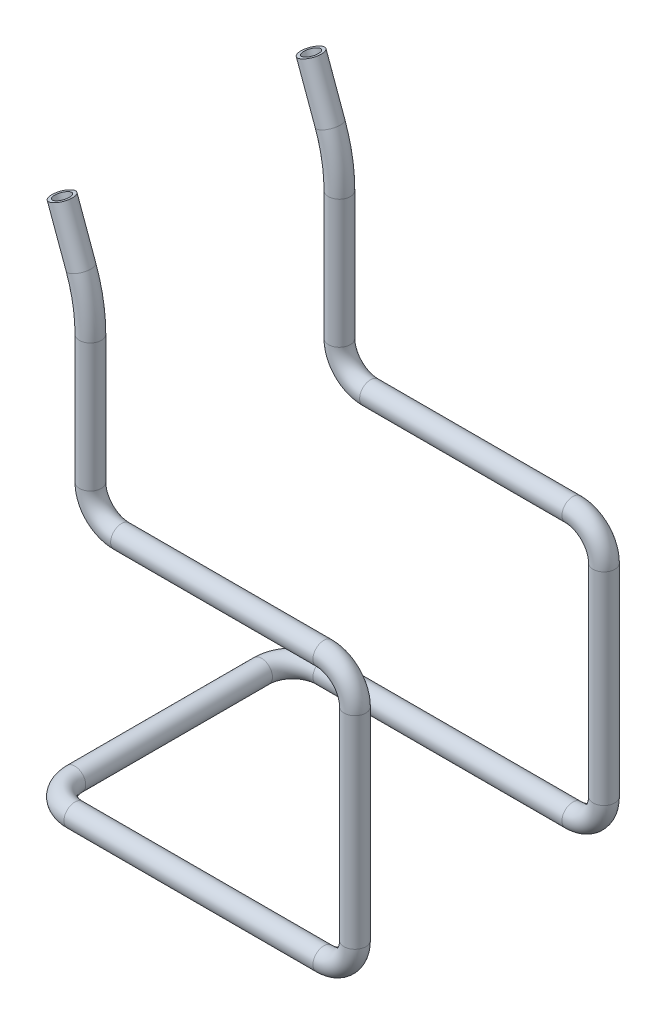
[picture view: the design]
ISO-10303-21;
HEADER;
FILE_DESCRIPTION(('STEP AP214'),'2;1');
FILE_NAME('part.step','',(''),(''),'','','');
FILE_SCHEMA(('AUTOMOTIVE_DESIGN { 1 0 10303 214 1 1 1 1 }'));
ENDSEC;
DATA;
#1=APPLICATION_CONTEXT('core data for automotive mechanical design processes');
#2=APPLICATION_PROTOCOL_DEFINITION('international standard','automotive_design',2000,#1);
#3=PRODUCT_CONTEXT('',#1,'mechanical');
#4=PRODUCT('Part','Part','',(#3));
#5=PRODUCT_RELATED_PRODUCT_CATEGORY('part','',(#4));
#6=PRODUCT_DEFINITION_FORMATION('','',#4);
#7=PRODUCT_DEFINITION_CONTEXT('part definition',#1,'design');
#8=PRODUCT_DEFINITION('design','',#6,#7);
#9=PRODUCT_DEFINITION_SHAPE('','',#8);
#10=(LENGTH_UNIT() NAMED_UNIT(*) SI_UNIT(.MILLI.,.METRE.));
#11=(NAMED_UNIT(*) PLANE_ANGLE_UNIT() SI_UNIT($,.RADIAN.));
#12=(NAMED_UNIT(*) SI_UNIT($,.STERADIAN.) SOLID_ANGLE_UNIT());
#13=UNCERTAINTY_MEASURE_WITH_UNIT(LENGTH_MEASURE(1.E-05),#10,'distance_accuracy_value','');
#14=(GEOMETRIC_REPRESENTATION_CONTEXT(3) GLOBAL_UNCERTAINTY_ASSIGNED_CONTEXT((#13)) GLOBAL_UNIT_ASSIGNED_CONTEXT((#10,
#11,#12)) REPRESENTATION_CONTEXT('',''));
#15=CARTESIAN_POINT('',(0.,0.,0.));
#16=DIRECTION('',(0.,0.,1.));
#17=DIRECTION('',(1.,0.,0.));
#18=AXIS2_PLACEMENT_3D('',#15,#16,#17);
#19=CARTESIAN_POINT('',(11.9846310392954,153.28465813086,40.));
#20=DIRECTION('',(-0.34202014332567,0.939692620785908,0.));
#21=DIRECTION('',(-0.939692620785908,-0.34202014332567,0.));
#22=AXIS2_PLACEMENT_3D('',#19,#20,#21);
#23=CYLINDRICAL_SURFACE('',#22,3.5);
#24=CARTESIAN_POINT('',(11.9846310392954,153.28465813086,40.));
#25=DIRECTION('',(-0.34202014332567,0.939692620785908,0.));
#26=DIRECTION('',(-0.939692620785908,-0.34202014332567,0.));
#27=AXIS2_PLACEMENT_3D('',#24,#25,#26);
#28=CIRCLE('',#27,3.5);
#29=CARTESIAN_POINT('',(15.2735552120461,154.4817286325,39.9999999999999));
#30=VERTEX_POINT('',#29);
#31=EDGE_CURVE('E37',#30,#30,#28,.T.);
#32=ORIENTED_EDGE('',*,*,#31,.T.);
#33=EDGE_LOOP('',(#32));
#34=FACE_BOUND('',#33,.T.);
#35=CARTESIAN_POINT('',(5.90074414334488,170.,40.0000000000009));
#36=DIRECTION('',(-0.34202014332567,0.939692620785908,0.));
#37=DIRECTION('',(-0.939692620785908,-0.342020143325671,0.));
#38=AXIS2_PLACEMENT_3D('',#35,#36,#37);
#39=CIRCLE('',#38,3.5);
#40=CARTESIAN_POINT('',(2.61181997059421,168.80292949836,40.0000000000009));
#41=VERTEX_POINT('',#40);
#42=EDGE_CURVE('E10',#41,#41,#39,.T.);
#43=ORIENTED_EDGE('',*,*,#42,.F.);
#44=EDGE_LOOP('',(#43));
#45=FACE_BOUND('',#44,.T.);
#46=ADVANCED_FACE('F30',(#34,#45),#23,.T.);
#47=CARTESIAN_POINT('',(-35.,136.183650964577,40.0000000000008));
#48=DIRECTION('',(0.,0.,1.));
#49=DIRECTION('',(1.,0.,0.));
#50=AXIS2_PLACEMENT_3D('',#47,#48,#49);
#51=TOROIDAL_SURFACE('',#50,50.,3.5);
#52=CARTESIAN_POINT('',(15.,136.183650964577,39.9999999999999));
#53=DIRECTION('',(0.,-1.,0.));
#54=DIRECTION('',(0.,0.,-1.));
#55=AXIS2_PLACEMENT_3D('',#52,#53,#54);
#56=CIRCLE('',#55,3.5);
#57=CARTESIAN_POINT('',(18.5,136.183650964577,39.9999999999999));
#58=VERTEX_POINT('',#57);
#59=EDGE_CURVE('E41',#58,#58,#56,.F.);
#60=CARTESIAN_POINT('',(-35.,136.183650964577,40.0000000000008));
#61=DIRECTION('',(0.,0.,1.));
#62=DIRECTION('',(1.,0.,0.));
#63=AXIS2_PLACEMENT_3D('',#60,#61,#62);
#64=CIRCLE('',#63,53.5);
#65=EDGE_CURVE('',#58,#30,#64,.T.);
#66=ORIENTED_EDGE('',*,*,#59,.T.);
#67=ORIENTED_EDGE('',*,*,#31,.F.);
#68=ORIENTED_EDGE('',*,*,#65,.T.);
#69=ORIENTED_EDGE('',*,*,#65,.F.);
#70=EDGE_LOOP('',(#66,#68,#67,#69));
#71=FACE_BOUND('',#70,.T.);
#72=ADVANCED_FACE('F198',(#71),#51,.T.);
#73=CARTESIAN_POINT('',(15.,95.,40.));
#74=DIRECTION('',(0.,1.,0.));
#75=DIRECTION('',(0.,0.,1.));
#76=AXIS2_PLACEMENT_3D('',#73,#74,#75);
#77=CYLINDRICAL_SURFACE('',#76,3.5);
#78=CARTESIAN_POINT('',(15.,95.,40.));
#79=DIRECTION('',(0.,1.,0.));
#80=DIRECTION('',(0.,0.,1.));
#81=AXIS2_PLACEMENT_3D('',#78,#79,#80);
#82=CIRCLE('',#81,3.5);
#83=CARTESIAN_POINT('',(11.5,95.,40.));
#84=VERTEX_POINT('',#83);
#85=EDGE_CURVE('E46',#84,#84,#82,.T.);
#86=ORIENTED_EDGE('',*,*,#85,.T.);
#87=EDGE_LOOP('',(#86));
#88=FACE_BOUND('',#87,.T.);
#89=ORIENTED_EDGE('',*,*,#59,.F.);
#90=EDGE_LOOP('',(#89));
#91=FACE_BOUND('',#90,.T.);
#92=ADVANCED_FACE('F203',(#88,#91),#77,.T.);
#93=CARTESIAN_POINT('',(25.,95.,40.));
#94=DIRECTION('',(0.,0.,-1.));
#95=DIRECTION('',(-1.,0.,0.));
#96=AXIS2_PLACEMENT_3D('',#93,#94,#95);
#97=TOROIDAL_SURFACE('',#96,10.,3.5);
#98=CARTESIAN_POINT('',(25.,85.,40.));
#99=DIRECTION('',(1.,0.,0.));
#100=DIRECTION('',(0.,1.,0.));
#101=AXIS2_PLACEMENT_3D('',#98,#99,#100);
#102=CIRCLE('',#101,3.5);
#103=CARTESIAN_POINT('',(25.,81.5,40.));
#104=VERTEX_POINT('',#103);
#105=EDGE_CURVE('E54',#104,#104,#102,.F.);
#106=CARTESIAN_POINT('',(25.,95.,40.));
#107=DIRECTION('',(0.,0.,-1.));
#108=DIRECTION('',(-1.,0.,0.));
#109=AXIS2_PLACEMENT_3D('',#106,#107,#108);
#110=CIRCLE('',#109,13.5);
#111=EDGE_CURVE('',#104,#84,#110,.T.);
#112=ORIENTED_EDGE('',*,*,#105,.T.);
#113=ORIENTED_EDGE('',*,*,#85,.F.);
#114=ORIENTED_EDGE('',*,*,#111,.T.);
#115=ORIENTED_EDGE('',*,*,#111,.F.);
#116=EDGE_LOOP('',(#112,#114,#113,#115));
#117=FACE_BOUND('',#116,.T.);
#118=ADVANCED_FACE('F213',(#117),#97,.T.);
#119=CARTESIAN_POINT('',(90.,85.,40.));
#120=DIRECTION('',(-1.,0.,0.));
#121=DIRECTION('',(0.,0.,1.));
#122=AXIS2_PLACEMENT_3D('',#119,#120,#121);
#123=CYLINDRICAL_SURFACE('',#122,3.5);
#124=CARTESIAN_POINT('',(90.,85.,40.));
#125=DIRECTION('',(-1.,0.,0.));
#126=DIRECTION('',(0.,0.,1.));
#127=AXIS2_PLACEMENT_3D('',#124,#125,#126);
#128=CIRCLE('',#127,3.5);
#129=CARTESIAN_POINT('',(90.,88.5,40.));
#130=VERTEX_POINT('',#129);
#131=EDGE_CURVE('E57',#130,#130,#128,.T.);
#132=ORIENTED_EDGE('',*,*,#131,.T.);
#133=EDGE_LOOP('',(#132));
#134=FACE_BOUND('',#133,.T.);
#135=ORIENTED_EDGE('',*,*,#105,.F.);
#136=EDGE_LOOP('',(#135));
#137=FACE_BOUND('',#136,.T.);
#138=ADVANCED_FACE('F217',(#134,#137),#123,.T.);
#139=CARTESIAN_POINT('',(90.,75.,40.));
#140=DIRECTION('',(0.,0.,1.));
#141=DIRECTION('',(1.,0.,0.));
#142=AXIS2_PLACEMENT_3D('',#139,#140,#141);
#143=TOROIDAL_SURFACE('',#142,9.99999999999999,3.5);
#144=CARTESIAN_POINT('',(100.,75.,40.));
#145=DIRECTION('',(0.,-1.,0.));
#146=DIRECTION('',(1.,0.,0.));
#147=AXIS2_PLACEMENT_3D('',#144,#145,#146);
#148=CIRCLE('',#147,3.5);
#149=CARTESIAN_POINT('',(103.5,75.,40.));
#150=VERTEX_POINT('',#149);
#151=EDGE_CURVE('E60',#150,#150,#148,.F.);
#152=CARTESIAN_POINT('',(90.,75.,40.));
#153=DIRECTION('',(0.,0.,1.));
#154=DIRECTION('',(1.,0.,0.));
#155=AXIS2_PLACEMENT_3D('',#152,#153,#154);
#156=CIRCLE('',#155,13.5);
#157=EDGE_CURVE('',#150,#130,#156,.T.);
#158=ORIENTED_EDGE('',*,*,#151,.T.);
#159=ORIENTED_EDGE('',*,*,#131,.F.);
#160=ORIENTED_EDGE('',*,*,#157,.T.);
#161=ORIENTED_EDGE('',*,*,#157,.F.);
#162=EDGE_LOOP('',(#158,#160,#159,#161));
#163=FACE_BOUND('',#162,.T.);
#164=ADVANCED_FACE('F221',(#163),#143,.T.);
#165=CARTESIAN_POINT('',(100.,9.99999999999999,40.));
#166=DIRECTION('',(0.,1.,0.));
#167=DIRECTION('',(0.,0.,1.));
#168=AXIS2_PLACEMENT_3D('',#165,#166,#167);
#169=CYLINDRICAL_SURFACE('',#168,3.5);
#170=CARTESIAN_POINT('',(100.,9.99999999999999,40.));
#171=DIRECTION('',(0.,1.,0.));
#172=DIRECTION('',(0.,0.,1.));
#173=AXIS2_PLACEMENT_3D('',#170,#171,#172);
#174=CIRCLE('',#173,3.5);
#175=CARTESIAN_POINT('',(103.5,9.99999999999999,40.));
#176=VERTEX_POINT('',#175);
#177=EDGE_CURVE('E63',#176,#176,#174,.T.);
#178=ORIENTED_EDGE('',*,*,#177,.T.);
#179=EDGE_LOOP('',(#178));
#180=FACE_BOUND('',#179,.T.);
#181=ORIENTED_EDGE('',*,*,#151,.F.);
#182=EDGE_LOOP('',(#181));
#183=FACE_BOUND('',#182,.T.);
#184=ADVANCED_FACE('F225',(#180,#183),#169,.T.);
#185=CARTESIAN_POINT('',(90.,10.,40.));
#186=DIRECTION('',(0.,0.,1.));
#187=DIRECTION('',(1.,0.,0.));
#188=AXIS2_PLACEMENT_3D('',#185,#186,#187);
#189=TOROIDAL_SURFACE('',#188,10.,3.5);
#190=CARTESIAN_POINT('',(90.,0.,40.));
#191=DIRECTION('',(-1.,0.,0.));
#192=DIRECTION('',(0.,-1.,0.));
#193=AXIS2_PLACEMENT_3D('',#190,#191,#192);
#194=CIRCLE('',#193,3.5);
#195=CARTESIAN_POINT('',(90.,-3.5,40.));
#196=VERTEX_POINT('',#195);
#197=EDGE_CURVE('E66',#196,#196,#194,.F.);
#198=CARTESIAN_POINT('',(90.,10.,40.));
#199=DIRECTION('',(0.,0.,1.));
#200=DIRECTION('',(1.,0.,0.));
#201=AXIS2_PLACEMENT_3D('',#198,#199,#200);
#202=CIRCLE('',#201,13.5);
#203=EDGE_CURVE('',#196,#176,#202,.T.);
#204=ORIENTED_EDGE('',*,*,#197,.T.);
#205=ORIENTED_EDGE('',*,*,#177,.F.);
#206=ORIENTED_EDGE('',*,*,#203,.T.);
#207=ORIENTED_EDGE('',*,*,#203,.F.);
#208=EDGE_LOOP('',(#204,#206,#205,#207));
#209=FACE_BOUND('',#208,.T.);
#210=ADVANCED_FACE('F229',(#209),#189,.T.);
#211=CARTESIAN_POINT('',(10.,0.,40.));
#212=DIRECTION('',(1.,0.,0.));
#213=DIRECTION('',(0.,0.,-1.));
#214=AXIS2_PLACEMENT_3D('',#211,#212,#213);
#215=CYLINDRICAL_SURFACE('',#214,3.5);
#216=CARTESIAN_POINT('',(10.,0.,40.));
#217=DIRECTION('',(1.,0.,0.));
#218=DIRECTION('',(0.,0.,-1.));
#219=AXIS2_PLACEMENT_3D('',#216,#217,#218);
#220=CIRCLE('',#219,3.5);
#221=CARTESIAN_POINT('',(10.,0.,43.5));
#222=VERTEX_POINT('',#221);
#223=EDGE_CURVE('E69',#222,#222,#220,.T.);
#224=ORIENTED_EDGE('',*,*,#223,.T.);
#225=EDGE_LOOP('',(#224));
#226=FACE_BOUND('',#225,.T.);
#227=ORIENTED_EDGE('',*,*,#197,.F.);
#228=EDGE_LOOP('',(#227));
#229=FACE_BOUND('',#228,.T.);
#230=ADVANCED_FACE('F233',(#226,#229),#215,.T.);
#231=CARTESIAN_POINT('',(10.,0.,30.));
#232=DIRECTION('',(0.,1.,0.));
#233=DIRECTION('',(0.,0.,1.));
#234=AXIS2_PLACEMENT_3D('',#231,#232,#233);
#235=TOROIDAL_SURFACE('',#234,10.,3.5);
#236=CARTESIAN_POINT('',(0.,0.,30.));
#237=DIRECTION('',(0.,0.,-1.));
#238=DIRECTION('',(-1.,0.,0.));
#239=AXIS2_PLACEMENT_3D('',#236,#237,#238);
#240=CIRCLE('',#239,3.5);
#241=CARTESIAN_POINT('',(-3.5,0.,30.));
#242=VERTEX_POINT('',#241);
#243=EDGE_CURVE('E71',#242,#242,#240,.F.);
#244=CARTESIAN_POINT('',(10.,0.,30.));
#245=DIRECTION('',(0.,1.,0.));
#246=DIRECTION('',(0.,0.,1.));
#247=AXIS2_PLACEMENT_3D('',#244,#245,#246);
#248=CIRCLE('',#247,13.5);
#249=EDGE_CURVE('',#242,#222,#248,.T.);
#250=ORIENTED_EDGE('',*,*,#243,.T.);
#251=ORIENTED_EDGE('',*,*,#223,.F.);
#252=ORIENTED_EDGE('',*,*,#249,.T.);
#253=ORIENTED_EDGE('',*,*,#249,.F.);
#254=EDGE_LOOP('',(#250,#252,#251,#253));
#255=FACE_BOUND('',#254,.T.);
#256=ADVANCED_FACE('F236',(#255),#235,.T.);
#257=CARTESIAN_POINT('',(0.,0.,30.));
#258=DIRECTION('',(0.,0.,-1.));
#259=DIRECTION('',(-1.,0.,0.));
#260=AXIS2_PLACEMENT_3D('',#257,#258,#259);
#261=CYLINDRICAL_SURFACE('',#260,3.5);
#262=CARTESIAN_POINT('',(0.,0.,-30.));
#263=DIRECTION('',(0.,0.,-1.));
#264=DIRECTION('',(-1.,0.,0.));
#265=AXIS2_PLACEMENT_3D('',#262,#263,#264);
#266=CIRCLE('',#265,3.5);
#267=CARTESIAN_POINT('',(-3.5,0.,-30.));
#268=VERTEX_POINT('',#267);
#269=EDGE_CURVE('E114',#268,#268,#266,.F.);
#270=CARTESIAN_POINT('',(-3.5,0.,30.));
#271=CARTESIAN_POINT('',(-3.5,0.,29.375));
#272=CARTESIAN_POINT('',(-3.5,0.,28.75));
#273=CARTESIAN_POINT('',(-3.5,0.,27.5));
#274=CARTESIAN_POINT('',(-3.5,0.,26.875));
#275=CARTESIAN_POINT('',(-3.5,0.,25.625));
#276=CARTESIAN_POINT('',(-3.5,0.,25.));
#277=CARTESIAN_POINT('',(-3.5,0.,23.75));
#278=CARTESIAN_POINT('',(-3.5,0.,23.125));
#279=CARTESIAN_POINT('',(-3.5,0.,21.875));
#280=CARTESIAN_POINT('',(-3.5,0.,21.25));
#281=CARTESIAN_POINT('',(-3.5,0.,20.));
#282=CARTESIAN_POINT('',(-3.5,0.,19.375));
#283=CARTESIAN_POINT('',(-3.5,0.,18.125));
#284=CARTESIAN_POINT('',(-3.5,0.,17.5));
#285=CARTESIAN_POINT('',(-3.5,0.,16.25));
#286=CARTESIAN_POINT('',(-3.5,0.,15.625));
#287=CARTESIAN_POINT('',(-3.5,0.,14.375));
#288=CARTESIAN_POINT('',(-3.5,0.,13.75));
#289=CARTESIAN_POINT('',(-3.5,0.,12.5));
#290=CARTESIAN_POINT('',(-3.5,0.,11.875));
#291=CARTESIAN_POINT('',(-3.5,0.,10.625));
#292=CARTESIAN_POINT('',(-3.5,0.,10.));
#293=CARTESIAN_POINT('',(-3.5,0.,8.75));
#294=CARTESIAN_POINT('',(-3.5,0.,8.125));
#295=CARTESIAN_POINT('',(-3.5,0.,6.875));
#296=CARTESIAN_POINT('',(-3.5,0.,6.25));
#297=CARTESIAN_POINT('',(-3.5,0.,5.));
#298=CARTESIAN_POINT('',(-3.5,0.,4.375));
#299=CARTESIAN_POINT('',(-3.5,0.,3.125));
#300=CARTESIAN_POINT('',(-3.5,0.,2.5));
#301=CARTESIAN_POINT('',(-3.5,0.,1.25));
#302=CARTESIAN_POINT('',(-3.5,0.,0.624999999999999));
#303=CARTESIAN_POINT('',(-3.5,0.,-0.624999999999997));
#304=CARTESIAN_POINT('',(-3.5,0.,-1.24999999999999));
#305=CARTESIAN_POINT('',(-3.5,0.,-2.49999999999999));
#306=CARTESIAN_POINT('',(-3.5,0.,-3.12499999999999));
#307=CARTESIAN_POINT('',(-3.5,0.,-4.37499999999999));
#308=CARTESIAN_POINT('',(-3.5,0.,-4.99999999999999));
#309=CARTESIAN_POINT('',(-3.5,0.,-6.24999999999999));
#310=CARTESIAN_POINT('',(-3.5,0.,-6.87499999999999));
#311=CARTESIAN_POINT('',(-3.5,0.,-8.12499999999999));
#312=CARTESIAN_POINT('',(-3.5,0.,-8.74999999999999));
#313=CARTESIAN_POINT('',(-3.5,0.,-9.99999999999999));
#314=CARTESIAN_POINT('',(-3.5,0.,-10.625));
#315=CARTESIAN_POINT('',(-3.5,0.,-11.875));
#316=CARTESIAN_POINT('',(-3.5,0.,-12.5));
#317=CARTESIAN_POINT('',(-3.5,0.,-13.75));
#318=CARTESIAN_POINT('',(-3.5,0.,-14.375));
#319=CARTESIAN_POINT('',(-3.5,0.,-15.625));
#320=CARTESIAN_POINT('',(-3.5,0.,-16.25));
#321=CARTESIAN_POINT('',(-3.5,0.,-17.5));
#322=CARTESIAN_POINT('',(-3.5,0.,-18.125));
#323=CARTESIAN_POINT('',(-3.5,0.,-19.375));
#324=CARTESIAN_POINT('',(-3.5,0.,-20.));
#325=CARTESIAN_POINT('',(-3.5,0.,-21.25));
#326=CARTESIAN_POINT('',(-3.5,0.,-21.875));
#327=CARTESIAN_POINT('',(-3.5,0.,-23.125));
#328=CARTESIAN_POINT('',(-3.5,0.,-23.75));
#329=CARTESIAN_POINT('',(-3.5,0.,-25.));
#330=CARTESIAN_POINT('',(-3.5,0.,-25.625));
#331=CARTESIAN_POINT('',(-3.5,0.,-26.875));
#332=CARTESIAN_POINT('',(-3.5,0.,-27.5));
#333=CARTESIAN_POINT('',(-3.5,0.,-28.75));
#334=CARTESIAN_POINT('',(-3.5,0.,-29.375));
#335=CARTESIAN_POINT('',(-3.5,0.,-30.));
#336=B_SPLINE_CURVE_WITH_KNOTS('',3,(#270,#271,#272,#273,#274,#275,#276,#277,#278,#279,#280,
#281,#282,#283,#284,#285,#286,#287,#288,#289,#290,#291,#292,#293,#294,#295,#296,#297,#298,#299,
#300,#301,#302,#303,#304,#305,#306,#307,#308,#309,#310,#311,#312,#313,#314,#315,#316,#317,#318,
#319,#320,#321,#322,#323,#324,#325,#326,#327,#328,#329,#330,#331,#332,#333,#334,#335),
.UNSPECIFIED.,.F.,.F.,(4,2,2,2,2,2,2,2,2,2,2,2,2,2,2,2,2,2,2,2,2,2,2,2,2,2,2,2,2,2,2,2,4),(0.,
1.875,3.75,5.625,7.5,9.37499999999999,11.25,13.125,15.,16.875,18.75,20.625,22.5,24.375,26.25,
28.125,30.,31.875,33.75,35.625,37.5,39.375,41.25,43.125,45.,46.875,48.75,50.625,52.5,54.375,
56.25,58.125,60.),.UNSPECIFIED.);
#337=EDGE_CURVE('BSEAM32',#242,#268,#336,.T.);
#338=ORIENTED_EDGE('',*,*,#243,.F.);
#339=ORIENTED_EDGE('',*,*,#269,.T.);
#340=ORIENTED_EDGE('',*,*,#337,.T.);
#341=ORIENTED_EDGE('',*,*,#337,.F.);
#342=EDGE_LOOP('',(#338,#340,#339,#341));
#343=FACE_BOUND('',#342,.T.);
#344=ADVANCED_FACE('F32',(#343),#261,.T.);
#345=CARTESIAN_POINT('',(5.90074414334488,170.,40.0000000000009));
#346=DIRECTION('',(-0.34202014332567,0.939692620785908,0.));
#347=DIRECTION('',(0.,0.,-1.));
#348=AXIS2_PLACEMENT_3D('',#345,#346,#347);
#349=PLANE('',#348);
#350=CARTESIAN_POINT('',(5.90074414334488,170.,40.0000000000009));
#351=DIRECTION('',(-0.34202014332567,0.939692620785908,0.));
#352=DIRECTION('',(0.,0.,-1.));
#353=AXIS2_PLACEMENT_3D('',#350,#351,#352);
#354=CIRCLE('',#353,2.5);
#355=CARTESIAN_POINT('',(5.90074414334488,170.,37.5000000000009));
#356=VERTEX_POINT('',#355);
#357=EDGE_CURVE('E49',#356,#356,#354,.T.);
#358=ORIENTED_EDGE('',*,*,#357,.F.);
#359=EDGE_LOOP('',(#358));
#360=FACE_BOUND('',#359,.T.);
#361=ORIENTED_EDGE('',*,*,#42,.T.);
#362=EDGE_LOOP('',(#361));
#363=FACE_BOUND('',#362,.T.);
#364=ADVANCED_FACE('F208',(#360,#363),#349,.T.);
#365=CARTESIAN_POINT('',(11.9846310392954,153.28465813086,40.));
#366=DIRECTION('',(-0.34202014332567,0.939692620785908,0.));
#367=DIRECTION('',(-0.939692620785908,-0.34202014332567,0.));
#368=AXIS2_PLACEMENT_3D('',#365,#366,#367);
#369=CYLINDRICAL_SURFACE('',#368,2.5);
#370=CARTESIAN_POINT('',(11.9846310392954,153.28465813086,40.));
#371=DIRECTION('',(-0.34202014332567,0.939692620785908,0.));
#372=DIRECTION('',(0.,0.,-1.));
#373=AXIS2_PLACEMENT_3D('',#370,#371,#372);
#374=CIRCLE('',#373,2.5);
#375=CARTESIAN_POINT('',(14.3338625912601,154.139708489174,39.9999999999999));
#376=VERTEX_POINT('',#375);
#377=EDGE_CURVE('E76',#376,#376,#374,.T.);
#378=ORIENTED_EDGE('',*,*,#377,.F.);
#379=EDGE_LOOP('',(#378));
#380=FACE_BOUND('',#379,.T.);
#381=ORIENTED_EDGE('',*,*,#357,.T.);
#382=EDGE_LOOP('',(#381));
#383=FACE_BOUND('',#382,.T.);
#384=ADVANCED_FACE('F263',(#380,#383),#369,.F.);
#385=CARTESIAN_POINT('',(-35.,136.183650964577,40.0000000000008));
#386=DIRECTION('',(0.,0.,1.));
#387=DIRECTION('',(1.,0.,0.));
#388=AXIS2_PLACEMENT_3D('',#385,#386,#387);
#389=TOROIDAL_SURFACE('',#388,50.,2.5);
#390=CARTESIAN_POINT('',(15.,136.183650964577,39.9999999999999));
#391=DIRECTION('',(0.,1.,0.));
#392=DIRECTION('',(0.,0.,-1.));
#393=AXIS2_PLACEMENT_3D('',#390,#391,#392);
#394=CIRCLE('',#393,2.5);
#395=CARTESIAN_POINT('',(17.5,136.183650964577,39.9999999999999));
#396=VERTEX_POINT('',#395);
#397=EDGE_CURVE('E80',#396,#396,#394,.T.);
#398=CARTESIAN_POINT('',(-35.,136.183650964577,40.0000000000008));
#399=DIRECTION('',(0.,0.,1.));
#400=DIRECTION('',(1.,0.,0.));
#401=AXIS2_PLACEMENT_3D('',#398,#399,#400);
#402=CIRCLE('',#401,52.5);
#403=EDGE_CURVE('',#396,#376,#402,.T.);
#404=ORIENTED_EDGE('',*,*,#397,.F.);
#405=ORIENTED_EDGE('',*,*,#377,.T.);
#406=ORIENTED_EDGE('',*,*,#403,.T.);
#407=ORIENTED_EDGE('',*,*,#403,.F.);
#408=EDGE_LOOP('',(#404,#406,#405,#407));
#409=FACE_BOUND('',#408,.T.);
#410=ADVANCED_FACE('F541',(#409),#389,.F.);
#411=CARTESIAN_POINT('',(15.,95.,40.));
#412=DIRECTION('',(0.,1.,0.));
#413=DIRECTION('',(0.,0.,1.));
#414=AXIS2_PLACEMENT_3D('',#411,#412,#413);
#415=CYLINDRICAL_SURFACE('',#414,2.5);
#416=CARTESIAN_POINT('',(15.,95.,40.));
#417=DIRECTION('',(0.,1.,0.));
#418=DIRECTION('',(0.,0.,-1.));
#419=AXIS2_PLACEMENT_3D('',#416,#417,#418);
#420=CIRCLE('',#419,2.5);
#421=CARTESIAN_POINT('',(12.5,95.,40.));
#422=VERTEX_POINT('',#421);
#423=EDGE_CURVE('E84',#422,#422,#420,.T.);
#424=ORIENTED_EDGE('',*,*,#423,.F.);
#425=EDGE_LOOP('',(#424));
#426=FACE_BOUND('',#425,.T.);
#427=ORIENTED_EDGE('',*,*,#397,.T.);
#428=EDGE_LOOP('',(#427));
#429=FACE_BOUND('',#428,.T.);
#430=ADVANCED_FACE('F532',(#426,#429),#415,.F.);
#431=CARTESIAN_POINT('',(25.,95.,40.));
#432=DIRECTION('',(0.,0.,-1.));
#433=DIRECTION('',(-1.,0.,0.));
#434=AXIS2_PLACEMENT_3D('',#431,#432,#433);
#435=TOROIDAL_SURFACE('',#434,10.,2.5);
#436=CARTESIAN_POINT('',(25.,85.,40.));
#437=DIRECTION('',(-1.,0.,0.));
#438=DIRECTION('',(0.,0.,-1.));
#439=AXIS2_PLACEMENT_3D('',#436,#437,#438);
#440=CIRCLE('',#439,2.5);
#441=CARTESIAN_POINT('',(25.,82.5,40.));
#442=VERTEX_POINT('',#441);
#443=EDGE_CURVE('E89',#442,#442,#440,.T.);
#444=CARTESIAN_POINT('',(25.,95.,40.));
#445=DIRECTION('',(0.,0.,-1.));
#446=DIRECTION('',(-1.,0.,0.));
#447=AXIS2_PLACEMENT_3D('',#444,#445,#446);
#448=CIRCLE('',#447,12.5);
#449=EDGE_CURVE('',#442,#422,#448,.T.);
#450=ORIENTED_EDGE('',*,*,#443,.F.);
#451=ORIENTED_EDGE('',*,*,#423,.T.);
#452=ORIENTED_EDGE('',*,*,#449,.T.);
#453=ORIENTED_EDGE('',*,*,#449,.F.);
#454=EDGE_LOOP('',(#450,#452,#451,#453));
#455=FACE_BOUND('',#454,.T.);
#456=ADVANCED_FACE('F523',(#455),#435,.F.);
#457=CARTESIAN_POINT('',(90.,85.,40.));
#458=DIRECTION('',(-1.,0.,0.));
#459=DIRECTION('',(0.,0.,1.));
#460=AXIS2_PLACEMENT_3D('',#457,#458,#459);
#461=CYLINDRICAL_SURFACE('',#460,2.5);
#462=CARTESIAN_POINT('',(90.,85.,40.));
#463=DIRECTION('',(-1.,0.,0.));
#464=DIRECTION('',(0.,0.,-1.));
#465=AXIS2_PLACEMENT_3D('',#462,#463,#464);
#466=CIRCLE('',#465,2.5);
#467=CARTESIAN_POINT('',(90.,87.5,40.));
#468=VERTEX_POINT('',#467);
#469=EDGE_CURVE('E92',#468,#468,#466,.T.);
#470=ORIENTED_EDGE('',*,*,#469,.F.);
#471=EDGE_LOOP('',(#470));
#472=FACE_BOUND('',#471,.T.);
#473=ORIENTED_EDGE('',*,*,#443,.T.);
#474=EDGE_LOOP('',(#473));
#475=FACE_BOUND('',#474,.T.);
#476=ADVANCED_FACE('F514',(#472,#475),#461,.F.);
#477=CARTESIAN_POINT('',(90.,75.,40.));
#478=DIRECTION('',(0.,0.,1.));
#479=DIRECTION('',(1.,0.,0.));
#480=AXIS2_PLACEMENT_3D('',#477,#478,#479);
#481=TOROIDAL_SURFACE('',#480,9.99999999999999,2.5);
#482=CARTESIAN_POINT('',(100.,75.,40.));
#483=DIRECTION('',(0.,1.,0.));
#484=DIRECTION('',(0.,0.,-1.));
#485=AXIS2_PLACEMENT_3D('',#482,#483,#484);
#486=CIRCLE('',#485,2.5);
#487=CARTESIAN_POINT('',(102.5,75.,40.));
#488=VERTEX_POINT('',#487);
#489=EDGE_CURVE('E95',#488,#488,#486,.T.);
#490=CARTESIAN_POINT('',(90.,75.,40.));
#491=DIRECTION('',(0.,0.,1.));
#492=DIRECTION('',(1.,0.,0.));
#493=AXIS2_PLACEMENT_3D('',#490,#491,#492);
#494=CIRCLE('',#493,12.5);
#495=EDGE_CURVE('',#488,#468,#494,.T.);
#496=ORIENTED_EDGE('',*,*,#489,.F.);
#497=ORIENTED_EDGE('',*,*,#469,.T.);
#498=ORIENTED_EDGE('',*,*,#495,.T.);
#499=ORIENTED_EDGE('',*,*,#495,.F.);
#500=EDGE_LOOP('',(#496,#498,#497,#499));
#501=FACE_BOUND('',#500,.T.);
#502=ADVANCED_FACE('F505',(#501),#481,.F.);
#503=CARTESIAN_POINT('',(100.,9.99999999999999,40.));
#504=DIRECTION('',(0.,1.,0.));
#505=DIRECTION('',(0.,0.,1.));
#506=AXIS2_PLACEMENT_3D('',#503,#504,#505);
#507=CYLINDRICAL_SURFACE('',#506,2.5);
#508=CARTESIAN_POINT('',(100.,9.99999999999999,40.));
#509=DIRECTION('',(0.,1.,0.));
#510=DIRECTION('',(0.,0.,-1.));
#511=AXIS2_PLACEMENT_3D('',#508,#509,#510);
#512=CIRCLE('',#511,2.5);
#513=CARTESIAN_POINT('',(102.5,9.99999999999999,40.));
#514=VERTEX_POINT('',#513);
#515=EDGE_CURVE('E98',#514,#514,#512,.T.);
#516=ORIENTED_EDGE('',*,*,#515,.F.);
#517=EDGE_LOOP('',(#516));
#518=FACE_BOUND('',#517,.T.);
#519=ORIENTED_EDGE('',*,*,#489,.T.);
#520=EDGE_LOOP('',(#519));
#521=FACE_BOUND('',#520,.T.);
#522=ADVANCED_FACE('F496',(#518,#521),#507,.F.);
#523=CARTESIAN_POINT('',(90.,10.,40.));
#524=DIRECTION('',(0.,0.,1.));
#525=DIRECTION('',(1.,0.,0.));
#526=AXIS2_PLACEMENT_3D('',#523,#524,#525);
#527=TOROIDAL_SURFACE('',#526,10.,2.5);
#528=CARTESIAN_POINT('',(90.,0.,40.));
#529=DIRECTION('',(1.,0.,0.));
#530=DIRECTION('',(0.,0.,-1.));
#531=AXIS2_PLACEMENT_3D('',#528,#529,#530);
#532=CIRCLE('',#531,2.5);
#533=CARTESIAN_POINT('',(90.,-2.5,40.));
#534=VERTEX_POINT('',#533);
#535=EDGE_CURVE('E101',#534,#534,#532,.T.);
#536=CARTESIAN_POINT('',(90.,10.,40.));
#537=DIRECTION('',(0.,0.,1.));
#538=DIRECTION('',(1.,0.,0.));
#539=AXIS2_PLACEMENT_3D('',#536,#537,#538);
#540=CIRCLE('',#539,12.5);
#541=EDGE_CURVE('',#534,#514,#540,.T.);
#542=ORIENTED_EDGE('',*,*,#535,.F.);
#543=ORIENTED_EDGE('',*,*,#515,.T.);
#544=ORIENTED_EDGE('',*,*,#541,.T.);
#545=ORIENTED_EDGE('',*,*,#541,.F.);
#546=EDGE_LOOP('',(#542,#544,#543,#545));
#547=FACE_BOUND('',#546,.T.);
#548=ADVANCED_FACE('F487',(#547),#527,.F.);
#549=CARTESIAN_POINT('',(10.,0.,40.));
#550=DIRECTION('',(1.,0.,0.));
#551=DIRECTION('',(0.,0.,-1.));
#552=AXIS2_PLACEMENT_3D('',#549,#550,#551);
#553=CYLINDRICAL_SURFACE('',#552,2.5);
#554=CARTESIAN_POINT('',(10.,0.,40.));
#555=DIRECTION('',(1.,0.,0.));
#556=DIRECTION('',(0.,0.,-1.));
#557=AXIS2_PLACEMENT_3D('',#554,#555,#556);
#558=CIRCLE('',#557,2.5);
#559=CARTESIAN_POINT('',(10.,0.,42.5));
#560=VERTEX_POINT('',#559);
#561=EDGE_CURVE('E104',#560,#560,#558,.T.);
#562=ORIENTED_EDGE('',*,*,#561,.F.);
#563=EDGE_LOOP('',(#562));
#564=FACE_BOUND('',#563,.T.);
#565=ORIENTED_EDGE('',*,*,#535,.T.);
#566=EDGE_LOOP('',(#565));
#567=FACE_BOUND('',#566,.T.);
#568=ADVANCED_FACE('F193',(#564,#567),#553,.F.);
#569=CARTESIAN_POINT('',(10.,0.,30.));
#570=DIRECTION('',(0.,1.,0.));
#571=DIRECTION('',(0.,0.,1.));
#572=AXIS2_PLACEMENT_3D('',#569,#570,#571);
#573=TOROIDAL_SURFACE('',#572,10.,2.5);
#574=CARTESIAN_POINT('',(0.,0.,30.));
#575=DIRECTION('',(0.,0.,1.));
#576=DIRECTION('',(1.,0.,0.));
#577=AXIS2_PLACEMENT_3D('',#574,#575,#576);
#578=CIRCLE('',#577,2.5);
#579=CARTESIAN_POINT('',(-2.5,0.,30.));
#580=VERTEX_POINT('',#579);
#581=EDGE_CURVE('E107',#580,#580,#578,.T.);
#582=CARTESIAN_POINT('',(10.,0.,30.));
#583=DIRECTION('',(0.,1.,0.));
#584=DIRECTION('',(0.,0.,1.));
#585=AXIS2_PLACEMENT_3D('',#582,#583,#584);
#586=CIRCLE('',#585,12.5);
#587=EDGE_CURVE('',#580,#560,#586,.T.);
#588=ORIENTED_EDGE('',*,*,#581,.F.);
#589=ORIENTED_EDGE('',*,*,#561,.T.);
#590=ORIENTED_EDGE('',*,*,#587,.T.);
#591=ORIENTED_EDGE('',*,*,#587,.F.);
#592=EDGE_LOOP('',(#588,#590,#589,#591));
#593=FACE_BOUND('',#592,.T.);
#594=ADVANCED_FACE('F183',(#593),#573,.F.);
#595=CARTESIAN_POINT('',(0.,0.,30.));
#596=DIRECTION('',(0.,0.,-1.));
#597=DIRECTION('',(-1.,0.,0.));
#598=AXIS2_PLACEMENT_3D('',#595,#596,#597);
#599=CYLINDRICAL_SURFACE('',#598,2.5);
#600=CARTESIAN_POINT('',(0.,0.,-30.));
#601=DIRECTION('',(0.,0.,1.));
#602=DIRECTION('',(1.,0.,0.));
#603=AXIS2_PLACEMENT_3D('',#600,#601,#602);
#604=CIRCLE('',#603,2.5);
#605=CARTESIAN_POINT('',(-2.5,0.,-30.));
#606=VERTEX_POINT('',#605);
#607=EDGE_CURVE('E173',#606,#606,#604,.T.);
#608=CARTESIAN_POINT('',(-2.5,0.,30.));
#609=CARTESIAN_POINT('',(-2.5,0.,29.375));
#610=CARTESIAN_POINT('',(-2.5,0.,28.75));
#611=CARTESIAN_POINT('',(-2.5,0.,27.5));
#612=CARTESIAN_POINT('',(-2.5,0.,26.875));
#613=CARTESIAN_POINT('',(-2.5,0.,25.625));
#614=CARTESIAN_POINT('',(-2.5,0.,25.));
#615=CARTESIAN_POINT('',(-2.5,0.,23.75));
#616=CARTESIAN_POINT('',(-2.5,0.,23.125));
#617=CARTESIAN_POINT('',(-2.5,0.,21.875));
#618=CARTESIAN_POINT('',(-2.5,0.,21.25));
#619=CARTESIAN_POINT('',(-2.5,0.,20.));
#620=CARTESIAN_POINT('',(-2.5,0.,19.375));
#621=CARTESIAN_POINT('',(-2.5,0.,18.125));
#622=CARTESIAN_POINT('',(-2.5,0.,17.5));
#623=CARTESIAN_POINT('',(-2.5,0.,16.25));
#624=CARTESIAN_POINT('',(-2.5,0.,15.625));
#625=CARTESIAN_POINT('',(-2.5,0.,14.375));
#626=CARTESIAN_POINT('',(-2.5,0.,13.75));
#627=CARTESIAN_POINT('',(-2.5,0.,12.5));
#628=CARTESIAN_POINT('',(-2.5,0.,11.875));
#629=CARTESIAN_POINT('',(-2.5,0.,10.625));
#630=CARTESIAN_POINT('',(-2.5,0.,10.));
#631=CARTESIAN_POINT('',(-2.5,0.,8.75));
#632=CARTESIAN_POINT('',(-2.5,0.,8.125));
#633=CARTESIAN_POINT('',(-2.5,0.,6.875));
#634=CARTESIAN_POINT('',(-2.5,0.,6.25));
#635=CARTESIAN_POINT('',(-2.5,0.,5.));
#636=CARTESIAN_POINT('',(-2.5,0.,4.375));
#637=CARTESIAN_POINT('',(-2.5,0.,3.125));
#638=CARTESIAN_POINT('',(-2.5,0.,2.5));
#639=CARTESIAN_POINT('',(-2.5,0.,1.25));
#640=CARTESIAN_POINT('',(-2.5,0.,0.625));
#641=CARTESIAN_POINT('',(-2.5,0.,-0.624999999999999));
#642=CARTESIAN_POINT('',(-2.5,0.,-1.25));
#643=CARTESIAN_POINT('',(-2.5,0.,-2.5));
#644=CARTESIAN_POINT('',(-2.5,0.,-3.125));
#645=CARTESIAN_POINT('',(-2.5,0.,-4.375));
#646=CARTESIAN_POINT('',(-2.5,0.,-5.));
#647=CARTESIAN_POINT('',(-2.5,0.,-6.25));
#648=CARTESIAN_POINT('',(-2.5,0.,-6.875));
#649=CARTESIAN_POINT('',(-2.5,0.,-8.125));
#650=CARTESIAN_POINT('',(-2.5,0.,-8.75));
#651=CARTESIAN_POINT('',(-2.5,0.,-10.));
#652=CARTESIAN_POINT('',(-2.5,0.,-10.625));
#653=CARTESIAN_POINT('',(-2.5,0.,-11.875));
#654=CARTESIAN_POINT('',(-2.5,0.,-12.5));
#655=CARTESIAN_POINT('',(-2.5,0.,-13.75));
#656=CARTESIAN_POINT('',(-2.5,0.,-14.375));
#657=CARTESIAN_POINT('',(-2.5,0.,-15.625));
#658=CARTESIAN_POINT('',(-2.5,0.,-16.25));
#659=CARTESIAN_POINT('',(-2.5,0.,-17.5));
#660=CARTESIAN_POINT('',(-2.5,0.,-18.125));
#661=CARTESIAN_POINT('',(-2.5,0.,-19.375));
#662=CARTESIAN_POINT('',(-2.5,0.,-20.));
#663=CARTESIAN_POINT('',(-2.5,0.,-21.25));
#664=CARTESIAN_POINT('',(-2.5,0.,-21.875));
#665=CARTESIAN_POINT('',(-2.5,0.,-23.125));
#666=CARTESIAN_POINT('',(-2.5,0.,-23.75));
#667=CARTESIAN_POINT('',(-2.5,0.,-25.));
#668=CARTESIAN_POINT('',(-2.5,0.,-25.625));
#669=CARTESIAN_POINT('',(-2.5,0.,-26.875));
#670=CARTESIAN_POINT('',(-2.5,0.,-27.5));
#671=CARTESIAN_POINT('',(-2.5,0.,-28.75));
#672=CARTESIAN_POINT('',(-2.5,0.,-29.375));
#673=CARTESIAN_POINT('',(-2.5,0.,-30.));
#674=B_SPLINE_CURVE_WITH_KNOTS('',3,(#608,#609,#610,#611,#612,#613,#614,#615,#616,#617,#618,
#619,#620,#621,#622,#623,#624,#625,#626,#627,#628,#629,#630,#631,#632,#633,#634,#635,#636,#637,
#638,#639,#640,#641,#642,#643,#644,#645,#646,#647,#648,#649,#650,#651,#652,#653,#654,#655,#656,
#657,#658,#659,#660,#661,#662,#663,#664,#665,#666,#667,#668,#669,#670,#671,#672,#673),
.UNSPECIFIED.,.F.,.F.,(4,2,2,2,2,2,2,2,2,2,2,2,2,2,2,2,2,2,2,2,2,2,2,2,2,2,2,2,2,2,2,2,4),(0.,
1.875,3.75,5.625,7.5,9.375,11.25,13.125,15.,16.875,18.75,20.625,22.5,24.375,26.25,28.125,30.,
31.875,33.75,35.625,37.5,39.375,41.25,43.125,45.,46.875,48.75,50.625,52.5,54.375,56.25,58.125,
60.),.UNSPECIFIED.);
#675=EDGE_CURVE('BSEAM180',#580,#606,#674,.T.);
#676=ORIENTED_EDGE('',*,*,#581,.T.);
#677=ORIENTED_EDGE('',*,*,#607,.F.);
#678=ORIENTED_EDGE('',*,*,#675,.T.);
#679=ORIENTED_EDGE('',*,*,#675,.F.);
#680=EDGE_LOOP('',(#676,#678,#677,#679));
#681=FACE_BOUND('',#680,.T.);
#682=ADVANCED_FACE('F180',(#681),#599,.F.);
#683=CARTESIAN_POINT('',(11.9846310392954,153.28465813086,-40.));
#684=DIRECTION('',(-0.34202014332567,0.939692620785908,0.));
#685=DIRECTION('',(-0.939692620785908,-0.34202014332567,0.));
#686=AXIS2_PLACEMENT_3D('',#683,#684,#685);
#687=CYLINDRICAL_SURFACE('',#686,3.5);
#688=CARTESIAN_POINT('',(11.9846310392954,153.28465813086,-40.));
#689=DIRECTION('',(0.34202014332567,-0.939692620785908,0.));
#690=DIRECTION('',(-0.939692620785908,-0.34202014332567,0.));
#691=AXIS2_PLACEMENT_3D('',#688,#689,#690);
#692=CIRCLE('',#691,3.5);
#693=CARTESIAN_POINT('',(15.2735552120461,154.4817286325,-39.9999999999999));
#694=VERTEX_POINT('',#693);
#695=EDGE_CURVE('E113',#694,#694,#692,.T.);
#696=ORIENTED_EDGE('',*,*,#695,.F.);
#697=EDGE_LOOP('',(#696));
#698=FACE_BOUND('',#697,.T.);
#699=CARTESIAN_POINT('',(5.90074414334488,170.,-40.0000000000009));
#700=DIRECTION('',(0.34202014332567,-0.939692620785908,0.));
#701=DIRECTION('',(-0.939692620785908,-0.342020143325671,0.));
#702=AXIS2_PLACEMENT_3D('',#699,#700,#701);
#703=CIRCLE('',#702,3.5);
#704=CARTESIAN_POINT('',(2.61181997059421,168.80292949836,-40.0000000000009));
#705=VERTEX_POINT('',#704);
#706=EDGE_CURVE('E110',#705,#705,#703,.T.);
#707=ORIENTED_EDGE('',*,*,#706,.T.);
#708=EDGE_LOOP('',(#707));
#709=FACE_BOUND('',#708,.T.);
#710=ADVANCED_FACE('F182',(#698,#709),#687,.T.);
#711=CARTESIAN_POINT('',(-35.,136.183650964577,-40.0000000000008));
#712=DIRECTION('',(0.,0.,-1.));
#713=DIRECTION('',(1.,0.,0.));
#714=AXIS2_PLACEMENT_3D('',#711,#712,#713);
#715=TOROIDAL_SURFACE('',#714,50.,3.5);
#716=CARTESIAN_POINT('',(15.,136.183650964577,-39.9999999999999));
#717=DIRECTION('',(0.,1.,0.));
#718=DIRECTION('',(0.,0.,1.));
#719=AXIS2_PLACEMENT_3D('',#716,#717,#718);
#720=CIRCLE('',#719,3.5);
#721=CARTESIAN_POINT('',(18.5,136.183650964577,-39.9999999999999));
#722=VERTEX_POINT('',#721);
#723=EDGE_CURVE('E139',#722,#722,#720,.F.);
#724=CARTESIAN_POINT('',(-35.,136.183650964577,-40.0000000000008));
#725=DIRECTION('',(0.,0.,-1.));
#726=DIRECTION('',(1.,0.,0.));
#727=AXIS2_PLACEMENT_3D('',#724,#725,#726);
#728=CIRCLE('',#727,53.5);
#729=EDGE_CURVE('',#694,#722,#728,.T.);
#730=ORIENTED_EDGE('',*,*,#695,.T.);
#731=ORIENTED_EDGE('',*,*,#723,.F.);
#732=ORIENTED_EDGE('',*,*,#729,.T.);
#733=ORIENTED_EDGE('',*,*,#729,.F.);
#734=EDGE_LOOP('',(#730,#732,#731,#733));
#735=FACE_BOUND('',#734,.T.);
#736=ADVANCED_FACE('F190',(#735),#715,.T.);
#737=CARTESIAN_POINT('',(15.,95.,-40.));
#738=DIRECTION('',(0.,1.,0.));
#739=DIRECTION('',(0.,0.,-1.));
#740=AXIS2_PLACEMENT_3D('',#737,#738,#739);
#741=CYLINDRICAL_SURFACE('',#740,3.5);
#742=CARTESIAN_POINT('',(15.,95.,-40.));
#743=DIRECTION('',(0.,-1.,0.));
#744=DIRECTION('',(0.,0.,-1.));
#745=AXIS2_PLACEMENT_3D('',#742,#743,#744);
#746=CIRCLE('',#745,3.5);
#747=CARTESIAN_POINT('',(11.5,95.,-40.));
#748=VERTEX_POINT('',#747);
#749=EDGE_CURVE('E136',#748,#748,#746,.T.);
#750=ORIENTED_EDGE('',*,*,#749,.F.);
#751=EDGE_LOOP('',(#750));
#752=FACE_BOUND('',#751,.T.);
#753=ORIENTED_EDGE('',*,*,#723,.T.);
#754=EDGE_LOOP('',(#753));
#755=FACE_BOUND('',#754,.T.);
#756=ADVANCED_FACE('F307',(#752,#755),#741,.T.);
#757=CARTESIAN_POINT('',(25.,95.,-40.));
#758=DIRECTION('',(0.,0.,1.));
#759=DIRECTION('',(-1.,0.,0.));
#760=AXIS2_PLACEMENT_3D('',#757,#758,#759);
#761=TOROIDAL_SURFACE('',#760,10.,3.5);
#762=CARTESIAN_POINT('',(25.,85.,-40.));
#763=DIRECTION('',(-1.,0.,0.));
#764=DIRECTION('',(0.,1.,0.));
#765=AXIS2_PLACEMENT_3D('',#762,#763,#764);
#766=CIRCLE('',#765,3.5);
#767=CARTESIAN_POINT('',(25.,81.5,-40.));
#768=VERTEX_POINT('',#767);
#769=EDGE_CURVE('E133',#768,#768,#766,.F.);
#770=CARTESIAN_POINT('',(25.,95.,-40.));
#771=DIRECTION('',(0.,0.,1.));
#772=DIRECTION('',(-1.,0.,0.));
#773=AXIS2_PLACEMENT_3D('',#770,#771,#772);
#774=CIRCLE('',#773,13.5);
#775=EDGE_CURVE('',#748,#768,#774,.T.);
#776=ORIENTED_EDGE('',*,*,#749,.T.);
#777=ORIENTED_EDGE('',*,*,#769,.F.);
#778=ORIENTED_EDGE('',*,*,#775,.T.);
#779=ORIENTED_EDGE('',*,*,#775,.F.);
#780=EDGE_LOOP('',(#776,#778,#777,#779));
#781=FACE_BOUND('',#780,.T.);
#782=ADVANCED_FACE('F301',(#781),#761,.T.);
#783=CARTESIAN_POINT('',(90.,85.,-40.));
#784=DIRECTION('',(-1.,0.,0.));
#785=DIRECTION('',(0.,0.,-1.));
#786=AXIS2_PLACEMENT_3D('',#783,#784,#785);
#787=CYLINDRICAL_SURFACE('',#786,3.5);
#788=CARTESIAN_POINT('',(90.,85.,-40.));
#789=DIRECTION('',(1.,0.,0.));
#790=DIRECTION('',(0.,0.,-1.));
#791=AXIS2_PLACEMENT_3D('',#788,#789,#790);
#792=CIRCLE('',#791,3.5);
#793=CARTESIAN_POINT('',(90.,88.5,-40.));
#794=VERTEX_POINT('',#793);
#795=EDGE_CURVE('E130',#794,#794,#792,.T.);
#796=ORIENTED_EDGE('',*,*,#795,.F.);
#797=EDGE_LOOP('',(#796));
#798=FACE_BOUND('',#797,.T.);
#799=ORIENTED_EDGE('',*,*,#769,.T.);
#800=EDGE_LOOP('',(#799));
#801=FACE_BOUND('',#800,.T.);
#802=ADVANCED_FACE('F295',(#798,#801),#787,.T.);
#803=CARTESIAN_POINT('',(90.,75.,-40.));
#804=DIRECTION('',(0.,0.,-1.));
#805=DIRECTION('',(1.,0.,0.));
#806=AXIS2_PLACEMENT_3D('',#803,#804,#805);
#807=TOROIDAL_SURFACE('',#806,9.99999999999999,3.5);
#808=CARTESIAN_POINT('',(100.,75.,-40.));
#809=DIRECTION('',(0.,1.,0.));
#810=DIRECTION('',(1.,0.,0.));
#811=AXIS2_PLACEMENT_3D('',#808,#809,#810);
#812=CIRCLE('',#811,3.5);
#813=CARTESIAN_POINT('',(103.5,75.,-40.));
#814=VERTEX_POINT('',#813);
#815=EDGE_CURVE('E127',#814,#814,#812,.F.);
#816=CARTESIAN_POINT('',(90.,75.,-40.));
#817=DIRECTION('',(0.,0.,-1.));
#818=DIRECTION('',(1.,0.,0.));
#819=AXIS2_PLACEMENT_3D('',#816,#817,#818);
#820=CIRCLE('',#819,13.5);
#821=EDGE_CURVE('',#794,#814,#820,.T.);
#822=ORIENTED_EDGE('',*,*,#795,.T.);
#823=ORIENTED_EDGE('',*,*,#815,.F.);
#824=ORIENTED_EDGE('',*,*,#821,.T.);
#825=ORIENTED_EDGE('',*,*,#821,.F.);
#826=EDGE_LOOP('',(#822,#824,#823,#825));
#827=FACE_BOUND('',#826,.T.);
#828=ADVANCED_FACE('F289',(#827),#807,.T.);
#829=CARTESIAN_POINT('',(100.,9.99999999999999,-40.));
#830=DIRECTION('',(0.,1.,0.));
#831=DIRECTION('',(0.,0.,-1.));
#832=AXIS2_PLACEMENT_3D('',#829,#830,#831);
#833=CYLINDRICAL_SURFACE('',#832,3.5);
#834=CARTESIAN_POINT('',(100.,9.99999999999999,-40.));
#835=DIRECTION('',(0.,-1.,0.));
#836=DIRECTION('',(0.,0.,-1.));
#837=AXIS2_PLACEMENT_3D('',#834,#835,#836);
#838=CIRCLE('',#837,3.5);
#839=CARTESIAN_POINT('',(103.5,9.99999999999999,-40.));
#840=VERTEX_POINT('',#839);
#841=EDGE_CURVE('E124',#840,#840,#838,.T.);
#842=ORIENTED_EDGE('',*,*,#841,.F.);
#843=EDGE_LOOP('',(#842));
#844=FACE_BOUND('',#843,.T.);
#845=ORIENTED_EDGE('',*,*,#815,.T.);
#846=EDGE_LOOP('',(#845));
#847=FACE_BOUND('',#846,.T.);
#848=ADVANCED_FACE('F283',(#844,#847),#833,.T.);
#849=CARTESIAN_POINT('',(90.,10.,-40.));
#850=DIRECTION('',(0.,0.,-1.));
#851=DIRECTION('',(1.,0.,0.));
#852=AXIS2_PLACEMENT_3D('',#849,#850,#851);
#853=TOROIDAL_SURFACE('',#852,10.,3.5);
#854=CARTESIAN_POINT('',(90.,0.,-40.));
#855=DIRECTION('',(1.,0.,0.));
#856=DIRECTION('',(0.,-1.,0.));
#857=AXIS2_PLACEMENT_3D('',#854,#855,#856);
#858=CIRCLE('',#857,3.5);
#859=CARTESIAN_POINT('',(90.,-3.5,-40.));
#860=VERTEX_POINT('',#859);
#861=EDGE_CURVE('E121',#860,#860,#858,.F.);
#862=CARTESIAN_POINT('',(90.,10.,-40.));
#863=DIRECTION('',(0.,0.,-1.));
#864=DIRECTION('',(1.,0.,0.));
#865=AXIS2_PLACEMENT_3D('',#862,#863,#864);
#866=CIRCLE('',#865,13.5);
#867=EDGE_CURVE('',#840,#860,#866,.T.);
#868=ORIENTED_EDGE('',*,*,#841,.T.);
#869=ORIENTED_EDGE('',*,*,#861,.F.);
#870=ORIENTED_EDGE('',*,*,#867,.T.);
#871=ORIENTED_EDGE('',*,*,#867,.F.);
#872=EDGE_LOOP('',(#868,#870,#869,#871));
#873=FACE_BOUND('',#872,.T.);
#874=ADVANCED_FACE('F277',(#873),#853,.T.);
#875=CARTESIAN_POINT('',(10.,0.,-40.));
#876=DIRECTION('',(1.,0.,0.));
#877=DIRECTION('',(0.,0.,1.));
#878=AXIS2_PLACEMENT_3D('',#875,#876,#877);
#879=CYLINDRICAL_SURFACE('',#878,3.5);
#880=CARTESIAN_POINT('',(10.,0.,-40.));
#881=DIRECTION('',(-1.,0.,0.));
#882=DIRECTION('',(0.,0.,1.));
#883=AXIS2_PLACEMENT_3D('',#880,#881,#882);
#884=CIRCLE('',#883,3.5);
#885=CARTESIAN_POINT('',(10.,0.,-43.5));
#886=VERTEX_POINT('',#885);
#887=EDGE_CURVE('E117',#886,#886,#884,.T.);
#888=ORIENTED_EDGE('',*,*,#887,.F.);
#889=EDGE_LOOP('',(#888));
#890=FACE_BOUND('',#889,.T.);
#891=ORIENTED_EDGE('',*,*,#861,.T.);
#892=EDGE_LOOP('',(#891));
#893=FACE_BOUND('',#892,.T.);
#894=ADVANCED_FACE('F272',(#890,#893),#879,.T.);
#895=CARTESIAN_POINT('',(10.,0.,-30.));
#896=DIRECTION('',(0.,1.,0.));
#897=DIRECTION('',(0.,0.,-1.));
#898=AXIS2_PLACEMENT_3D('',#895,#896,#897);
#899=TOROIDAL_SURFACE('',#898,10.,3.5);
#900=CARTESIAN_POINT('',(10.,0.,-30.));
#901=DIRECTION('',(0.,1.,0.));
#902=DIRECTION('',(0.,0.,-1.));
#903=AXIS2_PLACEMENT_3D('',#900,#901,#902);
#904=CIRCLE('',#903,13.5);
#905=EDGE_CURVE('',#886,#268,#904,.T.);
#906=ORIENTED_EDGE('',*,*,#887,.T.);
#907=ORIENTED_EDGE('',*,*,#269,.F.);
#908=ORIENTED_EDGE('',*,*,#905,.T.);
#909=ORIENTED_EDGE('',*,*,#905,.F.);
#910=EDGE_LOOP('',(#906,#908,#907,#909));
#911=FACE_BOUND('',#910,.T.);
#912=ADVANCED_FACE('F268',(#911),#899,.T.);
#913=CARTESIAN_POINT('',(5.90074414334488,170.,-40.0000000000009));
#914=DIRECTION('',(-0.34202014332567,0.939692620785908,0.));
#915=DIRECTION('',(0.,0.,1.));
#916=AXIS2_PLACEMENT_3D('',#913,#914,#915);
#917=PLANE('',#916);
#918=CARTESIAN_POINT('',(5.90074414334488,170.,-40.0000000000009));
#919=DIRECTION('',(0.34202014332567,-0.939692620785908,0.));
#920=DIRECTION('',(0.,0.,1.));
#921=AXIS2_PLACEMENT_3D('',#918,#919,#920);
#922=CIRCLE('',#921,2.5);
#923=CARTESIAN_POINT('',(5.90074414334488,170.,-37.5000000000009));
#924=VERTEX_POINT('',#923);
#925=EDGE_CURVE('E118',#924,#924,#922,.T.);
#926=ORIENTED_EDGE('',*,*,#925,.T.);
#927=EDGE_LOOP('',(#926));
#928=FACE_BOUND('',#927,.T.);
#929=ORIENTED_EDGE('',*,*,#706,.F.);
#930=EDGE_LOOP('',(#929));
#931=FACE_BOUND('',#930,.T.);
#932=ADVANCED_FACE('F271',(#928,#931),#917,.T.);
#933=CARTESIAN_POINT('',(11.9846310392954,153.28465813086,-40.));
#934=DIRECTION('',(-0.34202014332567,0.939692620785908,0.));
#935=DIRECTION('',(-0.939692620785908,-0.34202014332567,0.));
#936=AXIS2_PLACEMENT_3D('',#933,#934,#935);
#937=CYLINDRICAL_SURFACE('',#936,2.5);
#938=CARTESIAN_POINT('',(11.9846310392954,153.28465813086,-40.));
#939=DIRECTION('',(0.34202014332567,-0.939692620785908,0.));
#940=DIRECTION('',(0.,0.,1.));
#941=AXIS2_PLACEMENT_3D('',#938,#939,#940);
#942=CIRCLE('',#941,2.5);
#943=CARTESIAN_POINT('',(14.3338625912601,154.139708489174,-39.9999999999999));
#944=VERTEX_POINT('',#943);
#945=EDGE_CURVE('E146',#944,#944,#942,.T.);
#946=ORIENTED_EDGE('',*,*,#945,.T.);
#947=EDGE_LOOP('',(#946));
#948=FACE_BOUND('',#947,.T.);
#949=ORIENTED_EDGE('',*,*,#925,.F.);
#950=EDGE_LOOP('',(#949));
#951=FACE_BOUND('',#950,.T.);
#952=ADVANCED_FACE('F324',(#948,#951),#937,.F.);
#953=CARTESIAN_POINT('',(-35.,136.183650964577,-40.0000000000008));
#954=DIRECTION('',(0.,0.,-1.));
#955=DIRECTION('',(1.,0.,0.));
#956=AXIS2_PLACEMENT_3D('',#953,#954,#955);
#957=TOROIDAL_SURFACE('',#956,50.,2.5);
#958=CARTESIAN_POINT('',(15.,136.183650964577,-39.9999999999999));
#959=DIRECTION('',(0.,-1.,0.));
#960=DIRECTION('',(0.,0.,1.));
#961=AXIS2_PLACEMENT_3D('',#958,#959,#960);
#962=CIRCLE('',#961,2.5);
#963=CARTESIAN_POINT('',(17.5,136.183650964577,-39.9999999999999));
#964=VERTEX_POINT('',#963);
#965=EDGE_CURVE('E149',#964,#964,#962,.T.);
#966=CARTESIAN_POINT('',(-35.,136.183650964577,-40.0000000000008));
#967=DIRECTION('',(0.,0.,-1.));
#968=DIRECTION('',(1.,0.,0.));
#969=AXIS2_PLACEMENT_3D('',#966,#967,#968);
#970=CIRCLE('',#969,52.5);
#971=EDGE_CURVE('',#944,#964,#970,.T.);
#972=ORIENTED_EDGE('',*,*,#945,.F.);
#973=ORIENTED_EDGE('',*,*,#965,.T.);
#974=ORIENTED_EDGE('',*,*,#971,.T.);
#975=ORIENTED_EDGE('',*,*,#971,.F.);
#976=EDGE_LOOP('',(#972,#974,#973,#975));
#977=FACE_BOUND('',#976,.T.);
#978=ADVANCED_FACE('F330',(#977),#957,.F.);
#979=CARTESIAN_POINT('',(15.,95.,-40.));
#980=DIRECTION('',(0.,1.,0.));
#981=DIRECTION('',(0.,0.,-1.));
#982=AXIS2_PLACEMENT_3D('',#979,#980,#981);
#983=CYLINDRICAL_SURFACE('',#982,2.5);
#984=CARTESIAN_POINT('',(15.,95.,-40.));
#985=DIRECTION('',(0.,-1.,0.));
#986=DIRECTION('',(0.,0.,1.));
#987=AXIS2_PLACEMENT_3D('',#984,#985,#986);
#988=CIRCLE('',#987,2.5);
#989=CARTESIAN_POINT('',(12.5,95.,-40.));
#990=VERTEX_POINT('',#989);
#991=EDGE_CURVE('E152',#990,#990,#988,.T.);
#992=ORIENTED_EDGE('',*,*,#991,.T.);
#993=EDGE_LOOP('',(#992));
#994=FACE_BOUND('',#993,.T.);
#995=ORIENTED_EDGE('',*,*,#965,.F.);
#996=EDGE_LOOP('',(#995));
#997=FACE_BOUND('',#996,.T.);
#998=ADVANCED_FACE('F336',(#994,#997),#983,.F.);
#999=CARTESIAN_POINT('',(25.,95.,-40.));
#1000=DIRECTION('',(0.,0.,1.));
#1001=DIRECTION('',(-1.,0.,0.));
#1002=AXIS2_PLACEMENT_3D('',#999,#1000,#1001);
#1003=TOROIDAL_SURFACE('',#1002,10.,2.5);
#1004=CARTESIAN_POINT('',(25.,85.,-40.));
#1005=DIRECTION('',(1.,0.,0.));
#1006=DIRECTION('',(0.,0.,1.));
#1007=AXIS2_PLACEMENT_3D('',#1004,#1005,#1006);
#1008=CIRCLE('',#1007,2.5);
#1009=CARTESIAN_POINT('',(25.,82.5,-40.));
#1010=VERTEX_POINT('',#1009);
#1011=EDGE_CURVE('E155',#1010,#1010,#1008,.T.);
#1012=CARTESIAN_POINT('',(25.,95.,-40.));
#1013=DIRECTION('',(0.,0.,1.));
#1014=DIRECTION('',(-1.,0.,0.));
#1015=AXIS2_PLACEMENT_3D('',#1012,#1013,#1014);
#1016=CIRCLE('',#1015,12.5);
#1017=EDGE_CURVE('',#990,#1010,#1016,.T.);
#1018=ORIENTED_EDGE('',*,*,#991,.F.);
#1019=ORIENTED_EDGE('',*,*,#1011,.T.);
#1020=ORIENTED_EDGE('',*,*,#1017,.T.);
#1021=ORIENTED_EDGE('',*,*,#1017,.F.);
#1022=EDGE_LOOP('',(#1018,#1020,#1019,#1021));
#1023=FACE_BOUND('',#1022,.T.);
#1024=ADVANCED_FACE('F340',(#1023),#1003,.F.);
#1025=CARTESIAN_POINT('',(90.,85.,-40.));
#1026=DIRECTION('',(-1.,0.,0.));
#1027=DIRECTION('',(0.,0.,-1.));
#1028=AXIS2_PLACEMENT_3D('',#1025,#1026,#1027);
#1029=CYLINDRICAL_SURFACE('',#1028,2.5);
#1030=CARTESIAN_POINT('',(90.,85.,-40.));
#1031=DIRECTION('',(1.,0.,0.));
#1032=DIRECTION('',(0.,0.,1.));
#1033=AXIS2_PLACEMENT_3D('',#1030,#1031,#1032);
#1034=CIRCLE('',#1033,2.5);
#1035=CARTESIAN_POINT('',(90.,87.5,-40.));
#1036=VERTEX_POINT('',#1035);
#1037=EDGE_CURVE('E158',#1036,#1036,#1034,.T.);
#1038=ORIENTED_EDGE('',*,*,#1037,.T.);
#1039=EDGE_LOOP('',(#1038));
#1040=FACE_BOUND('',#1039,.T.);
#1041=ORIENTED_EDGE('',*,*,#1011,.F.);
#1042=EDGE_LOOP('',(#1041));
#1043=FACE_BOUND('',#1042,.T.);
#1044=ADVANCED_FACE('F344',(#1040,#1043),#1029,.F.);
#1045=CARTESIAN_POINT('',(90.,75.,-40.));
#1046=DIRECTION('',(0.,0.,-1.));
#1047=DIRECTION('',(1.,0.,0.));
#1048=AXIS2_PLACEMENT_3D('',#1045,#1046,#1047);
#1049=TOROIDAL_SURFACE('',#1048,9.99999999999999,2.5);
#1050=CARTESIAN_POINT('',(100.,75.,-40.));
#1051=DIRECTION('',(0.,-1.,0.));
#1052=DIRECTION('',(0.,0.,1.));
#1053=AXIS2_PLACEMENT_3D('',#1050,#1051,#1052);
#1054=CIRCLE('',#1053,2.5);
#1055=CARTESIAN_POINT('',(102.5,75.,-40.));
#1056=VERTEX_POINT('',#1055);
#1057=EDGE_CURVE('E161',#1056,#1056,#1054,.T.);
#1058=CARTESIAN_POINT('',(90.,75.,-40.));
#1059=DIRECTION('',(0.,0.,-1.));
#1060=DIRECTION('',(1.,0.,0.));
#1061=AXIS2_PLACEMENT_3D('',#1058,#1059,#1060);
#1062=CIRCLE('',#1061,12.5);
#1063=EDGE_CURVE('',#1036,#1056,#1062,.T.);
#1064=ORIENTED_EDGE('',*,*,#1037,.F.);
#1065=ORIENTED_EDGE('',*,*,#1057,.T.);
#1066=ORIENTED_EDGE('',*,*,#1063,.T.);
#1067=ORIENTED_EDGE('',*,*,#1063,.F.);
#1068=EDGE_LOOP('',(#1064,#1066,#1065,#1067));
#1069=FACE_BOUND('',#1068,.T.);
#1070=ADVANCED_FACE('F348',(#1069),#1049,.F.);
#1071=CARTESIAN_POINT('',(100.,9.99999999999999,-40.));
#1072=DIRECTION('',(0.,1.,0.));
#1073=DIRECTION('',(0.,0.,-1.));
#1074=AXIS2_PLACEMENT_3D('',#1071,#1072,#1073);
#1075=CYLINDRICAL_SURFACE('',#1074,2.5);
#1076=CARTESIAN_POINT('',(100.,9.99999999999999,-40.));
#1077=DIRECTION('',(0.,-1.,0.));
#1078=DIRECTION('',(0.,0.,1.));
#1079=AXIS2_PLACEMENT_3D('',#1076,#1077,#1078);
#1080=CIRCLE('',#1079,2.5);
#1081=CARTESIAN_POINT('',(102.5,9.99999999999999,-40.));
#1082=VERTEX_POINT('',#1081);
#1083=EDGE_CURVE('E164',#1082,#1082,#1080,.T.);
#1084=ORIENTED_EDGE('',*,*,#1083,.T.);
#1085=EDGE_LOOP('',(#1084));
#1086=FACE_BOUND('',#1085,.T.);
#1087=ORIENTED_EDGE('',*,*,#1057,.F.);
#1088=EDGE_LOOP('',(#1087));
#1089=FACE_BOUND('',#1088,.T.);
#1090=ADVANCED_FACE('F352',(#1086,#1089),#1075,.F.);
#1091=CARTESIAN_POINT('',(90.,10.,-40.));
#1092=DIRECTION('',(0.,0.,-1.));
#1093=DIRECTION('',(1.,0.,0.));
#1094=AXIS2_PLACEMENT_3D('',#1091,#1092,#1093);
#1095=TOROIDAL_SURFACE('',#1094,10.,2.5);
#1096=CARTESIAN_POINT('',(90.,0.,-40.));
#1097=DIRECTION('',(-1.,0.,0.));
#1098=DIRECTION('',(0.,0.,1.));
#1099=AXIS2_PLACEMENT_3D('',#1096,#1097,#1098);
#1100=CIRCLE('',#1099,2.5);
#1101=CARTESIAN_POINT('',(90.,-2.5,-40.));
#1102=VERTEX_POINT('',#1101);
#1103=EDGE_CURVE('E167',#1102,#1102,#1100,.T.);
#1104=CARTESIAN_POINT('',(90.,10.,-40.));
#1105=DIRECTION('',(0.,0.,-1.));
#1106=DIRECTION('',(1.,0.,0.));
#1107=AXIS2_PLACEMENT_3D('',#1104,#1105,#1106);
#1108=CIRCLE('',#1107,12.5);
#1109=EDGE_CURVE('',#1082,#1102,#1108,.T.);
#1110=ORIENTED_EDGE('',*,*,#1083,.F.);
#1111=ORIENTED_EDGE('',*,*,#1103,.T.);
#1112=ORIENTED_EDGE('',*,*,#1109,.T.);
#1113=ORIENTED_EDGE('',*,*,#1109,.F.);
#1114=EDGE_LOOP('',(#1110,#1112,#1111,#1113));
#1115=FACE_BOUND('',#1114,.T.);
#1116=ADVANCED_FACE('F356',(#1115),#1095,.F.);
#1117=CARTESIAN_POINT('',(10.,0.,-40.));
#1118=DIRECTION('',(1.,0.,0.));
#1119=DIRECTION('',(0.,0.,1.));
#1120=AXIS2_PLACEMENT_3D('',#1117,#1118,#1119);
#1121=CYLINDRICAL_SURFACE('',#1120,2.5);
#1122=CARTESIAN_POINT('',(10.,0.,-40.));
#1123=DIRECTION('',(-1.,0.,0.));
#1124=DIRECTION('',(0.,0.,1.));
#1125=AXIS2_PLACEMENT_3D('',#1122,#1123,#1124);
#1126=CIRCLE('',#1125,2.5);
#1127=CARTESIAN_POINT('',(10.,0.,-42.5));
#1128=VERTEX_POINT('',#1127);
#1129=EDGE_CURVE('E170',#1128,#1128,#1126,.T.);
#1130=ORIENTED_EDGE('',*,*,#1129,.T.);
#1131=EDGE_LOOP('',(#1130));
#1132=FACE_BOUND('',#1131,.T.);
#1133=ORIENTED_EDGE('',*,*,#1103,.F.);
#1134=EDGE_LOOP('',(#1133));
#1135=FACE_BOUND('',#1134,.T.);
#1136=ADVANCED_FACE('F360',(#1132,#1135),#1121,.F.);
#1137=CARTESIAN_POINT('',(10.,0.,-30.));
#1138=DIRECTION('',(0.,1.,0.));
#1139=DIRECTION('',(0.,0.,-1.));
#1140=AXIS2_PLACEMENT_3D('',#1137,#1138,#1139);
#1141=TOROIDAL_SURFACE('',#1140,10.,2.5);
#1142=CARTESIAN_POINT('',(10.,0.,-30.));
#1143=DIRECTION('',(0.,1.,0.));
#1144=DIRECTION('',(0.,0.,-1.));
#1145=AXIS2_PLACEMENT_3D('',#1142,#1143,#1144);
#1146=CIRCLE('',#1145,12.5);
#1147=EDGE_CURVE('',#1128,#606,#1146,.T.);
#1148=ORIENTED_EDGE('',*,*,#1129,.F.);
#1149=ORIENTED_EDGE('',*,*,#607,.T.);
#1150=ORIENTED_EDGE('',*,*,#1147,.T.);
#1151=ORIENTED_EDGE('',*,*,#1147,.F.);
#1152=EDGE_LOOP('',(#1148,#1150,#1149,#1151));
#1153=FACE_BOUND('',#1152,.T.);
#1154=ADVANCED_FACE('F177',(#1153),#1141,.F.);
#1155=CLOSED_SHELL('',(#46,#72,#92,#118,#138,#164,#184,#210,#230,#256,#344,#364,#384,#410,#430,
#456,#476,#502,#522,#548,#568,#594,#682,#710,#736,#756,#782,#802,#828,#848,#874,#894,#912,#932,
#952,#978,#998,#1024,#1044,#1070,#1090,#1116,#1136,#1154));
#1156=MANIFOLD_SOLID_BREP('B2',#1155);
#1157=ADVANCED_BREP_SHAPE_REPRESENTATION('',(#18,#1156),#14);
#1158=SHAPE_DEFINITION_REPRESENTATION(#9,#1157);
ENDSEC;
END-ISO-10303-21;
